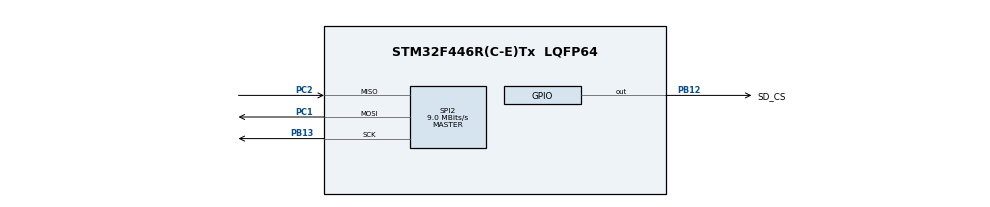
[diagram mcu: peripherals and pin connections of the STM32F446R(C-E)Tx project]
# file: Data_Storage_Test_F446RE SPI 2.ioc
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FATFS._MAX_SS=4096
FATFS._USE_LFN=1
Mcu.Family=STM32F4
Mcu.Name=STM32F446R(C-E)Tx
Mcu.Package=LQFP64
NVIC.PriorityGroup=NVIC_PRIORITYGROUP_4
NVIC.RCC_IRQn=true\:0\:0\:false\:false\:true\:true\:false\:true
PA13.Mode=Serial_Wire
PA13.Signal=SYS_JTMS-SWDIO
PA14.Mode=Serial_Wire
PA14.Signal=SYS_JTCK-SWCLK
PB12.GPIO_Label=SD_CS
PB12.Signal=GPIO_Output
PB13.Mode=Full_Duplex_Master
PB13.Signal=SPI2_SCK
PC1.Mode=Full_Duplex_Master
PC1.Signal=SPI2_MOSI
PC14-OSC32_IN.Mode=LSE-External-Oscillator
PC14-OSC32_IN.Signal=RCC_OSC32_IN
PC15-OSC32_OUT.Mode=LSE-External-Oscillator
PC15-OSC32_OUT.Signal=RCC_OSC32_OUT
PC2.Mode=Full_Duplex_Master
PC2.Signal=SPI2_MISO
PH0-OSC_IN.Mode=HSE-External-Oscillator
PH0-OSC_IN.Signal=RCC_OSC_IN
PH1-OSC_OUT.Mode=HSE-External-Oscillator
PH1-OSC_OUT.Signal=RCC_OSC_OUT
ProjectManager.HeapSize=0x200
ProjectManager.StackSize=0x400
ProjectManager.TargetToolchain=STM32CubeIDE
RCC.AHBFreq_Value=72000000
RCC.APB1CLKDivider=RCC_HCLK_DIV2
RCC.APB1Freq_Value=36000000
RCC.APB1TimFreq_Value=72000000
RCC.APB2CLKDivider=RCC_HCLK_DIV2
RCC.APB2Freq_Value=36000000
RCC.APB2TimFreq_Value=72000000
RCC.CortexFreq_Value=72000000
RCC.HCLKFreq_Value=72000000
RCC.HSE_VALUE=8000000
RCC.PLLM=8
RCC.PLLN=72
RCC.SYSCLKFreq_VALUE=72000000
RCC.SYSCLKSource=RCC_SYSCLKSOURCE_PLLRCLK
RCC.USBFreq_Value=72000000
RCC.VCOOutputFreq_Value=144000000
SPI2.BaudRatePrescaler=SPI_BAUDRATEPRESCALER_4
SPI2.CalculateBaudRate=9.0 MBits/s
SPI2.Direction=SPI_DIRECTION_2LINES
SPI2.Mode=SPI_MODE_MASTER
SPI2.VirtualType=VM_MASTER
VP_FATFS_VS_Generic.Mode=User_defined
board=custom

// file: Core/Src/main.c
/* USER CODE BEGIN Header */
/**
  ******************************************************************************
  * @file           : main.c
  * @brief          : Main program body
  ******************************************************************************
  * @attention
  *
  * Copyright (c) 2023 STMicroelectronics.
  * All rights reserved.
  *
  * This software is licensed under terms that can be found in the LICENSE file
  * in the root directory of this software component.
  * If no LICENSE file comes with this software, it is provided AS-IS.
  *
  ******************************************************************************
  */
/* USER CODE END Header */
#include "main.h"
#include "fatfs.h"

/* USER CODE BEGIN Includes */
#include "fatfs_sd.h"
#include "string.h"
#include <stdio.h>
/* USER CODE END Includes */

SPI_HandleTypeDef hspi2;

void SystemClock_Config(void);
static void MX_GPIO_Init(void);
static void MX_SPI2_Init(void);

/* USER CODE BEGIN 0 */
FATFS fs;  // file system
FIL fil; // File
FILINFO fno;
FRESULT fresult;  // result
UINT br, bw;  // File read/write count

#define BUFFER_SIZE 128
char buffer[BUFFER_SIZE];  // to store strings..

int i=0;

int bufsize (char *buf)
{
	int i=0;
	while (*buf++ != '\0') i++;
	return i;
}

void clear_buffer (void)
{
	for (int i=0; i<BUFFER_SIZE; i++) buffer[i] = '\0';
}

/* USER CODE END 0 */

int main(void)
{

  /* MCU Configuration--------------------------------------------------------*/

  /* Reset of all peripherals, Initializes the Flash interface and the Systick. */
  HAL_Init();

  /* Configure the system clock */
  SystemClock_Config();

  /* Initialize all configured peripherals */
  MX_GPIO_Init();
  MX_FATFS_Init();
  MX_SPI2_Init();
  /* USER CODE BEGIN 2 */
  HAL_Delay (500);

    fresult = f_mount(&fs, "/", 1);
    	if (fresult != FR_OK) printf ("ERROR!!! in mounting SD CARD...\n\n");
    	else printf("SD CARD mounted successfully...\n\n");

    	/* Create second file with read write access and open it */
    	  	fresult = f_open(&fil, "file7.txt", FA_CREATE_ALWAYS | FA_WRITE);

    	  	/* Writing text */
    	  	strcpy (buffer, "This is TestFile.txt, written using ...f_write... and it says Hello from Dutah\n");

    	  	fresult = f_write(&fil, buffer, bufsize(buffer), &bw);

    	  	printf ("File5.txt created and data is written\n");

    	  	/* Close file */
    	  	f_close(&fil);

    	  	// clearing buffer to show that result obtained is from the file
    	  	clear_buffer();

    	  	/* Open second file to read */
    	  	fresult = f_open(&fil, "file3.txt", FA_READ);
    	  	if (fresult == FR_OK)printf ("file2.txt is open and the data is shown below\n");

    	  	/* Read data from the file
    	  	 * Please see the function details for the arguments */
    	  	f_read (&fil, buffer, f_size(&fil), &br);
    	  	printf(buffer);
    	  	printf("\n\n");

    	  	/* Close file */
    	  	f_close(&fil);

    	  	clear_buffer();
  /* USER CODE END 2 */

  /* Infinite loop */
  while (1)
  {

  }
}

void SystemClock_Config(void)
{
  RCC_OscInitTypeDef RCC_OscInitStruct = {0};
  RCC_ClkInitTypeDef RCC_ClkInitStruct = {0};

  /** Configure the main internal regulator output voltage
  */
  __HAL_RCC_PWR_CLK_ENABLE();
  __HAL_PWR_VOLTAGESCALING_CONFIG(PWR_REGULATOR_VOLTAGE_SCALE3);

  /** Initializes the RCC Oscillators according to the specified parameters
  * in the RCC_OscInitTypeDef structure.
  */
  RCC_OscInitStruct.OscillatorType = RCC_OSCILLATORTYPE_HSE;
  RCC_OscInitStruct.HSEState = RCC_HSE_ON;
  RCC_OscInitStruct.PLL.PLLState = RCC_PLL_ON;
  RCC_OscInitStruct.PLL.PLLSource = RCC_PLLSOURCE_HSE;
  RCC_OscInitStruct.PLL.PLLM = 15;
  RCC_OscInitStruct.PLL.PLLN = 216;
  RCC_OscInitStruct.PLL.PLLP = RCC_PLLP_DIV2;
  RCC_OscInitStruct.PLL.PLLQ = 2;
  RCC_OscInitStruct.PLL.PLLR = 5;
  if (HAL_RCC_OscConfig(&RCC_OscInitStruct) != HAL_OK)
  {
    Error_Handler();
  }

  /** Initializes the CPU, AHB and APB buses clocks
  */
  RCC_ClkInitStruct.ClockType = RCC_CLOCKTYPE_HCLK|RCC_CLOCKTYPE_SYSCLK
                              |RCC_CLOCKTYPE_PCLK1|RCC_CLOCKTYPE_PCLK2;
  RCC_ClkInitStruct.SYSCLKSource = RCC_SYSCLKSOURCE_PLLRCLK;
  RCC_ClkInitStruct.AHBCLKDivider = RCC_SYSCLK_DIV1;
  RCC_ClkInitStruct.APB1CLKDivider = RCC_HCLK_DIV2;
  RCC_ClkInitStruct.APB2CLKDivider = RCC_HCLK_DIV2;

  if (HAL_RCC_ClockConfig(&RCC_ClkInitStruct, FLASH_LATENCY_2) != HAL_OK)
  {
    Error_Handler();
  }
}

static void MX_SPI2_Init(void)
{

  /* SPI2 parameter configuration*/
  hspi2.Instance = SPI2;
  hspi2.Init.Mode = SPI_MODE_MASTER;
  hspi2.Init.Direction = SPI_DIRECTION_2LINES;
  hspi2.Init.DataSize = SPI_DATASIZE_8BIT;
  hspi2.Init.CLKPolarity = SPI_POLARITY_LOW;
  hspi2.Init.CLKPhase = SPI_PHASE_1EDGE;
  hspi2.Init.NSS = SPI_NSS_SOFT;
  hspi2.Init.BaudRatePrescaler = SPI_BAUDRATEPRESCALER_4;
  hspi2.Init.FirstBit = SPI_FIRSTBIT_MSB;
  hspi2.Init.TIMode = SPI_TIMODE_DISABLE;
  hspi2.Init.CRCCalculation = SPI_CRCCALCULATION_DISABLE;
  hspi2.Init.CRCPolynomial = 10;
  if (HAL_SPI_Init(&hspi2) != HAL_OK)
  {
    Error_Handler();
  }

}

static void MX_GPIO_Init(void)
{
  GPIO_InitTypeDef GPIO_InitStruct = {0};

  /* GPIO Ports Clock Enable */
  __HAL_RCC_GPIOC_CLK_ENABLE();
  __HAL_RCC_GPIOH_CLK_ENABLE();
  __HAL_RCC_GPIOB_CLK_ENABLE();
  __HAL_RCC_GPIOA_CLK_ENABLE();

  /*Configure GPIO pin Output Level */
  HAL_GPIO_WritePin(SD_CS_GPIO_Port, SD_CS_Pin, GPIO_PIN_RESET);

  /*Configure GPIO pin : SD_CS_Pin */
  GPIO_InitStruct.Pin = SD_CS_Pin;
  GPIO_InitStruct.Mode = GPIO_MODE_OUTPUT_PP;
  GPIO_InitStruct.Pull = GPIO_NOPULL;
  GPIO_InitStruct.Speed = GPIO_SPEED_FREQ_LOW;
  HAL_GPIO_Init(SD_CS_GPIO_Port, &GPIO_InitStruct);

}

/* USER CODE BEGIN 4 */
int _write(int file, char *ptr, int len)
{
	int DataIdx;

	for (DataIdx = 0; DataIdx < len; DataIdx++)
	{
		ITM_SendChar(*ptr++);
	}
	return len;
}
/* USER CODE END 4 */

void Error_Handler(void)
{
  __disable_irq();
  while (1)
  {
  }
}
